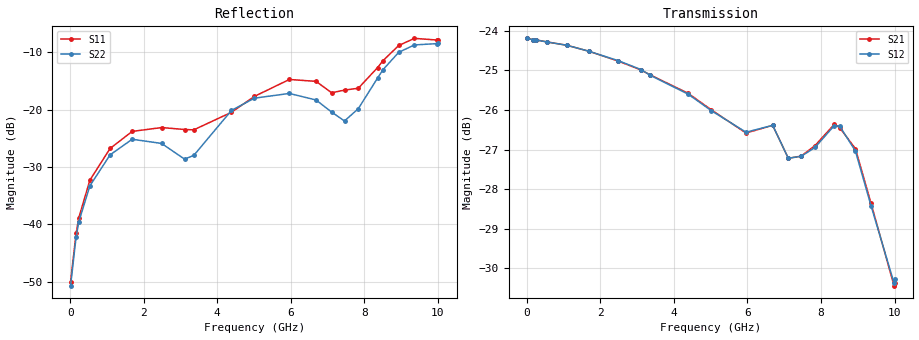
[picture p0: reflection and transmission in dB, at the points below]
! Device ID: PE43704
! Dir: z:\PE43704\PE43704_Char_1_20130516\PE43704\AMB\3p400V\23p25dB
! Serial: 14
! Insertion: A
! Impedance: 50 ohm
! Temp: Amb
! VDD: 3.400V
! Attenuation Step: 23.25dB
! IDD: 1.140097e-01mA
#  Hz  S  RI  R  50
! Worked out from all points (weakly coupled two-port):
!   401 points, 10 MHz to 10.01 GHz, reference 50 ohm
!   highest |S21| = -24.19 dB at 10 MHz (marker M1); lowest = -30.4 dB at 9.985 GHz (marker M2)
!   lowest |S11| = -50.0 dB at 10 MHz (marker M3), VSWR 1.01, Z = 50.3 + j0.0412 ohm
!   |S11| at or under -10 dB: start of sweep to 8.718 GHz
!   |S22| runs from -50.7 to -8.4 dB; largest |S21 - S12| = 0.00079
!   S11 on the Smith chart (normalised r, x): 10 MHz: 1.01, +0.00; 7.46 GHz: 0.78, +0.15; 8.51 GHz: 0.81, +0.46; 9.36 GHz: 0.54, +0.49; 10.01 GHz: 0.47, +0.28
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1e7  0.00315 0.000409  0.0617 -0.000205  0.0617 -0.000219  0.0029 0.000425
1.6e8  0.00274 0.00789  0.0614 -0.00291  0.0614 -0.00285  0.00269 0.00728
2.35e8  0.00129 0.0114  0.0613 -0.00414  0.0613 -0.00409  0.00131 0.0105
5.35e8  -0.00725 0.0232  0.0604 -0.00909  0.0604 -0.00902  -0.00687 0.0206
1.085e9  -0.0352 0.0294  0.0578 -0.0178  0.0578 -0.0178  -0.0325 0.0239
1.685e9  -0.0626 0.0157  0.0533 -0.0263  0.0533 -0.0263  -0.0546 0.00778
2.485e9  -0.0695 -0.00592  0.0454 -0.0357  0.0455 -0.0357  -0.0503 -0.00653
3.11e9  -0.0668 -0.00587  0.038 -0.0415  0.0381 -0.0415  -0.0367 0.00505
3.36e9  -0.0666 -9.01e-05  0.0348 -0.0432  0.0348 -0.0431  -0.0373 0.0141
4.385e9  -0.084 0.0437  0.0224 -0.0476  0.0223 -0.0475  -0.0792 0.0582
5.01e9  -0.108 0.0728  0.0152 -0.0478  0.0151 -0.0477  -0.109 0.0626
5.96e9  -0.1554 0.0963  0.00498 -0.0466  0.00508 -0.0467  -0.1279 0.0523
6.685e9  -0.1554 0.0827  -0.00157 -0.0479  -0.00162 -0.0479  -0.1132 0.0432
7.11e9  -0.1245 0.0642  -0.00806 -0.0428  -0.00809 -0.0428  -0.08 0.0514
7.46e9  -0.114 0.094  -0.00847 -0.043  -0.00832 -0.043  -0.0514 0.0607
7.835e9  -0.0673 0.1378  -0.0107 -0.0439  -0.0105 -0.0437  -0.0362 0.0952
8.36e9  -0.0353 0.2294  -0.02 -0.0437  -0.0198 -0.0436  -0.0548 0.1801
8.51e9  -0.0383 0.2645  -0.0231 -0.0416  -0.0228 -0.042  -0.0692 0.2121
8.935e9  -0.0888 0.3502  -0.0288 -0.0343  -0.0288 -0.0339  -0.1401 0.2823
9.36e9  -0.1789 0.3763  -0.0278 -0.0262  -0.0279 -0.0257  -0.2334 0.2809
9.985e9  -0.3078 0.2598  -0.0189 -0.0234  -0.0194 -0.0233  -0.3555 0.1199
1.001e10  -0.3129 0.2516  -0.0189 -0.0237  -0.0194 -0.0238  -0.3596 0.111
